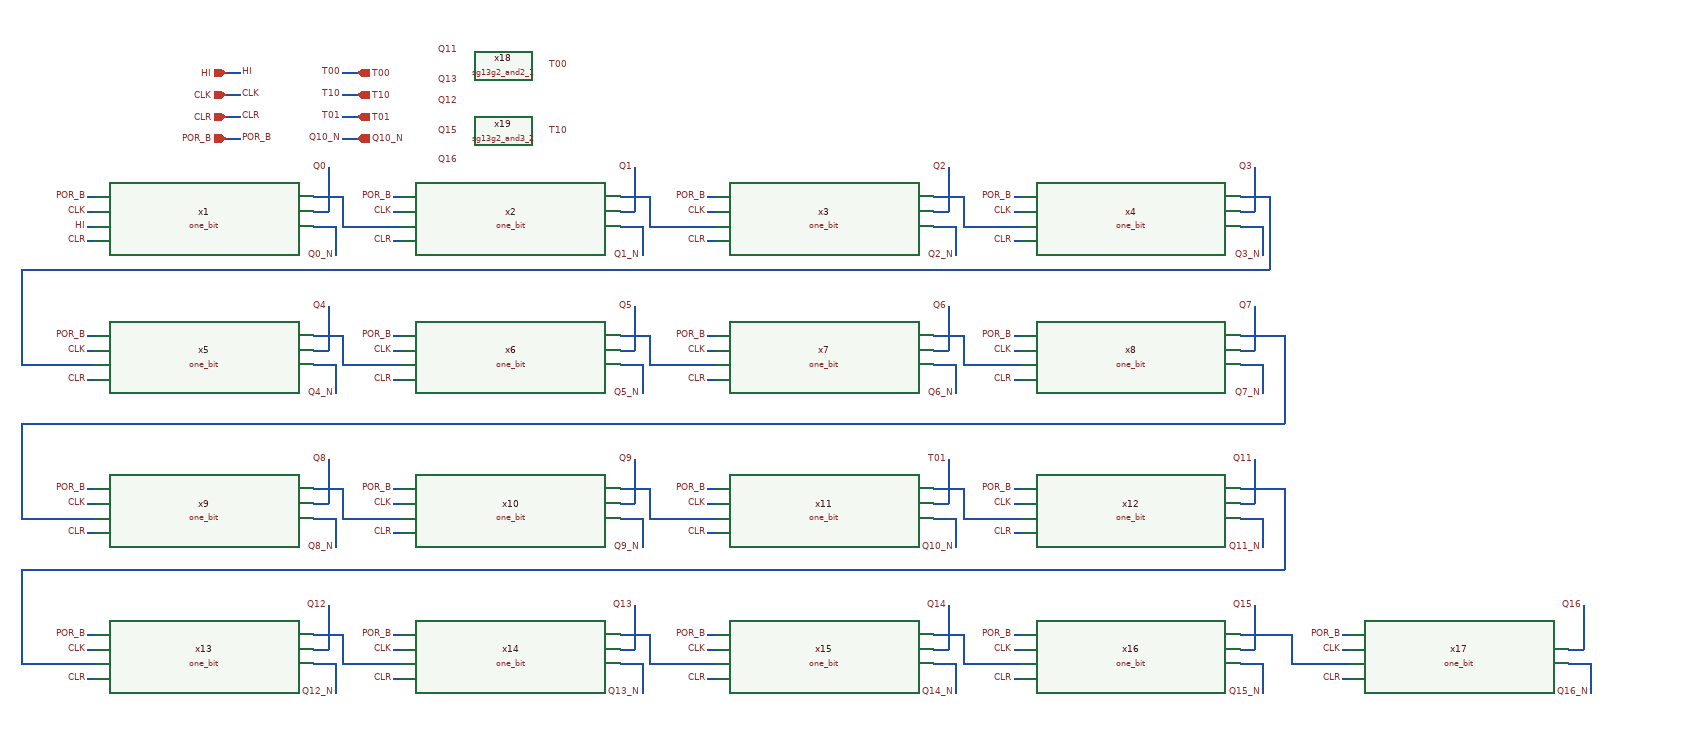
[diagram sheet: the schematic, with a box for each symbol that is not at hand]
v {xschem version=3.4.8RC file_version=1.3}
G {}
K {}
V {}
S {}
F {}
E {}
N -40 -30 0 -30 {lab=#net1}
N -160 -170 -140 -170 {lab=CLK}
N -160 -140 -140 -140 {lab=CLR}
N -160 -110 -140 -110 {lab=POR_B}
N -350 -30 -340 -30 {lab=POR_B}
N -350 -10 -340 -10 {lab=CLK}
N -350 30 -340 30 {lab=CLR}
N -40 -10 -20 -10 {lab=Q0}
N -20 -70 -20 -10 {lab=Q0}
N 380 -30 420 -30 {lab=#net2}
N 70 -30 80 -30 {lab=POR_B}
N 70 -10 80 -10 {lab=CLK}
N 70 30 80 30 {lab=CLR}
N 380 -10 400 -10 {lab=Q1}
N 400 -70 400 -10 {lab=Q1}
N 0 10 80 10 {lab=#net1}
N 0 -30 0 10 {lab=#net1}
N 810 -30 850 -30 {lab=#net3}
N 500 -30 510 -30 {lab=POR_B}
N 500 -10 510 -10 {lab=CLK}
N 500 30 510 30 {lab=CLR}
N 810 -10 830 -10 {lab=Q2}
N 830 -70 830 -10 {lab=Q2}
N 1230 -30 1270 -30 {lab=#net4}
N 920 -30 930 -30 {lab=POR_B}
N 920 -10 930 -10 {lab=CLK}
N 920 30 930 30 {lab=CLR}
N 1230 -10 1250 -10 {lab=Q3}
N 1250 -70 1250 -10 {lab=Q3}
N 850 10 930 10 {lab=#net3}
N 850 -30 850 10 {lab=#net3}
N 420 -30 420 10 {lab=#net2}
N 420 10 510 10 {lab=#net2}
N -40 160 0 160 {lab=#net5}
N -350 160 -340 160 {lab=POR_B}
N -350 180 -340 180 {lab=CLK}
N -350 220 -340 220 {lab=CLR}
N -40 180 -20 180 {lab=Q4}
N -20 120 -20 180 {lab=Q4}
N 380 160 420 160 {lab=#net6}
N 70 160 80 160 {lab=POR_B}
N 70 180 80 180 {lab=CLK}
N 70 220 80 220 {lab=CLR}
N 380 180 400 180 {lab=Q5}
N 400 120 400 180 {lab=Q5}
N 0 200 80 200 {lab=#net5}
N 0 160 0 200 {lab=#net5}
N 810 160 850 160 {lab=#net7}
N 500 160 510 160 {lab=POR_B}
N 500 180 510 180 {lab=CLK}
N 500 220 510 220 {lab=CLR}
N 810 180 830 180 {lab=Q6}
N 830 120 830 180 {lab=Q6}
N 1230 160 1290 160 {lab=#net8}
N 920 160 930 160 {lab=POR_B}
N 920 180 930 180 {lab=CLK}
N 920 220 930 220 {lab=CLR}
N 1230 180 1250 180 {lab=Q7}
N 1250 120 1250 180 {lab=Q7}
N 850 200 930 200 {lab=#net7}
N 850 160 850 200 {lab=#net7}
N 420 160 420 200 {lab=#net6}
N 420 200 510 200 {lab=#net6}
N 1270 -30 1270 70 {lab=#net4}
N -440 70 1270 70 {lab=#net4}
N -440 70 -440 200 {lab=#net4}
N -440 200 -340 200 {lab=#net4}
N -40 10 -10 10 {lab=Q0_N}
N -10 10 -10 50 {lab=Q0_N}
N 380 10 410 10 {lab=Q1_N}
N 410 10 410 50 {lab=Q1_N}
N 810 10 840 10 {lab=Q2_N}
N 840 10 840 50 {lab=Q2_N}
N 1230 10 1260 10 {lab=Q3_N}
N 1260 10 1260 50 {lab=Q3_N}
N 1230 200 1260 200 {lab=Q7_N}
N 1260 200 1260 240 {lab=Q7_N}
N 810 200 840 200 {lab=Q6_N}
N 840 200 840 240 {lab=Q6_N}
N 380 200 410 200 {lab=Q5_N}
N 410 200 410 240 {lab=Q5_N}
N -40 200 -10 200 {lab=Q4_N}
N -10 200 -10 240 {lab=Q4_N}
N -40 370 0 370 {lab=#net9}
N -350 370 -340 370 {lab=POR_B}
N -350 390 -340 390 {lab=CLK}
N -350 430 -340 430 {lab=CLR}
N -40 390 -20 390 {lab=Q8}
N -20 330 -20 390 {lab=Q8}
N 380 370 420 370 {lab=#net10}
N 70 370 80 370 {lab=POR_B}
N 70 390 80 390 {lab=CLK}
N 70 430 80 430 {lab=CLR}
N 380 390 400 390 {lab=Q9}
N 400 330 400 390 {lab=Q9}
N 0 410 80 410 {lab=#net9}
N 0 370 0 410 {lab=#net9}
N 810 370 850 370 {lab=#net11}
N 500 370 510 370 {lab=POR_B}
N 500 390 510 390 {lab=CLK}
N 500 430 510 430 {lab=CLR}
N 810 390 830 390 {lab=Q10}
N 830 330 830 390 {lab=Q10}
N 1230 370 1290 370 {lab=#net12}
N 920 370 930 370 {lab=POR_B}
N 920 390 930 390 {lab=CLK}
N 920 430 930 430 {lab=CLR}
N 1230 390 1250 390 {lab=Q11}
N 1250 330 1250 390 {lab=Q11}
N 850 410 930 410 {lab=#net11}
N 850 370 850 410 {lab=#net11}
N 420 370 420 410 {lab=#net10}
N 420 410 510 410 {lab=#net10}
N -440 280 -440 410 {lab=#net8}
N -440 410 -340 410 {lab=#net8}
N 1230 410 1260 410 {lab=Q11_N}
N 1260 410 1260 450 {lab=Q11_N}
N 810 410 840 410 {lab=Q10_N}
N 840 410 840 450 {lab=Q10_N}
N 380 410 410 410 {lab=Q9_N}
N 410 410 410 450 {lab=Q9_N}
N -40 410 -10 410 {lab=Q8_N}
N -10 410 -10 450 {lab=Q8_N}
N -440 280 1290 280 {lab=#net8}
N 1290 160 1290 280 {lab=#net8}
N -40 570 0 570 {lab=#net13}
N -350 570 -340 570 {lab=POR_B}
N -350 590 -340 590 {lab=CLK}
N -350 630 -340 630 {lab=CLR}
N -40 590 -20 590 {lab=Q12}
N -20 530 -20 590 {lab=Q12}
N 380 570 420 570 {lab=#net14}
N 70 570 80 570 {lab=POR_B}
N 70 590 80 590 {lab=CLK}
N 70 630 80 630 {lab=CLR}
N 380 590 400 590 {lab=Q13}
N 400 530 400 590 {lab=Q13}
N 0 610 80 610 {lab=#net13}
N 0 570 0 610 {lab=#net13}
N 810 570 850 570 {lab=#net15}
N 500 570 510 570 {lab=POR_B}
N 500 590 510 590 {lab=CLK}
N 500 630 510 630 {lab=CLR}
N 810 590 830 590 {lab=Q14}
N 830 530 830 590 {lab=Q14}
N 920 570 930 570 {lab=POR_B}
N 920 590 930 590 {lab=CLK}
N 920 630 930 630 {lab=CLR}
N 1230 590 1250 590 {lab=Q15}
N 1250 530 1250 590 {lab=Q15}
N 850 610 930 610 {lab=#net15}
N 850 570 850 610 {lab=#net15}
N 420 570 420 610 {lab=#net14}
N 420 610 510 610 {lab=#net14}
N -440 480 -440 610 {lab=#net12}
N -440 610 -340 610 {lab=#net12}
N 1230 610 1260 610 {lab=Q15_N}
N 1260 610 1260 650 {lab=Q15_N}
N 810 610 840 610 {lab=Q14_N}
N 840 610 840 650 {lab=Q14_N}
N 380 610 410 610 {lab=Q13_N}
N 410 610 410 650 {lab=Q13_N}
N -40 610 -10 610 {lab=Q12_N}
N -10 610 -10 650 {lab=Q12_N}
N -440 480 1290 480 {lab=#net12}
N 1290 370 1290 480 {lab=#net12}
N 1370 570 1380 570 {lab=POR_B}
N 1370 590 1380 590 {lab=CLK}
N 1370 630 1380 630 {lab=CLR}
N 1680 590 1700 590 {lab=Q16}
N 1700 530 1700 590 {lab=Q16}
N 1300 610 1380 610 {lab=#net16}
N 1300 570 1300 610 {lab=#net16}
N 1680 610 1710 610 {lab=Q16_N}
N 1710 610 1710 650 {lab=Q16_N}
N 1230 570 1300 570 {lab=#net16}
N -160 -200 -140 -200 {lab=HI}
N -350 10 -340 10 {lab=HI}
N 0 -200 20 -200 {lab=T00}
N 0 -170 20 -170 {lab=T10}
N 0 -140 20 -140 {lab=T01}
N 0 -110 20 -110 {lab=Q10_N}
C {one_bit.sym} -190 0 0 0 {name=x1 VDD=VDD VSS=VSS}
C {lab_pin.sym} -140 -170 0 1 {name=p12 sig_type=std_logic lab=CLK
}
C {ipin.sym} -160 -170 0 0 {name=p13 lab=CLK}
C {lab_pin.sym} -140 -140 0 1 {name=p1 sig_type=std_logic lab=CLR
}
C {ipin.sym} -160 -140 0 0 {name=p2 lab=CLR}
C {lab_pin.sym} -140 -110 0 1 {name=p3 sig_type=std_logic lab=POR_B
}
C {ipin.sym} -160 -110 0 0 {name=p4 lab=POR_B}
C {lab_pin.sym} -350 -30 0 0 {name=p5 sig_type=std_logic lab=POR_B
}
C {lab_pin.sym} -350 30 0 0 {name=p6 sig_type=std_logic lab=CLR
}
C {lab_pin.sym} -350 -10 0 0 {name=p7 sig_type=std_logic lab=CLK
}
C {lab_pin.sym} -20 -70 0 0 {name=p8 sig_type=std_logic lab=Q0
}
C {one_bit.sym} 230 0 0 0 {name=x2 VDD=VDD VSS=VSS}
C {lab_pin.sym} 70 -30 0 0 {name=p9 sig_type=std_logic lab=POR_B
}
C {lab_pin.sym} 70 30 0 0 {name=p10 sig_type=std_logic lab=CLR
}
C {lab_pin.sym} 70 -10 0 0 {name=p11 sig_type=std_logic lab=CLK
}
C {lab_pin.sym} 400 -70 0 0 {name=p14 sig_type=std_logic lab=Q1
}
C {one_bit.sym} 660 0 0 0 {name=x3 VDD=VDD VSS=VSS}
C {lab_pin.sym} 500 -30 0 0 {name=p15 sig_type=std_logic lab=POR_B
}
C {lab_pin.sym} 500 30 0 0 {name=p16 sig_type=std_logic lab=CLR
}
C {lab_pin.sym} 500 -10 0 0 {name=p17 sig_type=std_logic lab=CLK
}
C {lab_pin.sym} 830 -70 0 0 {name=p18 sig_type=std_logic lab=Q2
}
C {one_bit.sym} 1080 0 0 0 {name=x4 VDD=VDD VSS=VSS}
C {lab_pin.sym} 920 -30 0 0 {name=p19 sig_type=std_logic lab=POR_B
}
C {lab_pin.sym} 920 30 0 0 {name=p20 sig_type=std_logic lab=CLR
}
C {lab_pin.sym} 920 -10 0 0 {name=p21 sig_type=std_logic lab=CLK
}
C {lab_pin.sym} 1250 -70 0 0 {name=p22 sig_type=std_logic lab=Q3
}
C {one_bit.sym} -190 190 0 0 {name=x5 VDD=VDD VSS=VSS}
C {lab_pin.sym} -350 160 0 0 {name=p23 sig_type=std_logic lab=POR_B
}
C {lab_pin.sym} -350 220 0 0 {name=p24 sig_type=std_logic lab=CLR
}
C {lab_pin.sym} -350 180 0 0 {name=p25 sig_type=std_logic lab=CLK
}
C {lab_pin.sym} -20 120 0 0 {name=p26 sig_type=std_logic lab=Q4
}
C {one_bit.sym} 230 190 0 0 {name=x6 VDD=VDD VSS=VSS}
C {lab_pin.sym} 70 160 0 0 {name=p27 sig_type=std_logic lab=POR_B
}
C {lab_pin.sym} 70 220 0 0 {name=p28 sig_type=std_logic lab=CLR
}
C {lab_pin.sym} 70 180 0 0 {name=p29 sig_type=std_logic lab=CLK
}
C {lab_pin.sym} 400 120 0 0 {name=p30 sig_type=std_logic lab=Q5
}
C {one_bit.sym} 660 190 0 0 {name=x7 VDD=VDD VSS=VSS}
C {lab_pin.sym} 500 160 0 0 {name=p31 sig_type=std_logic lab=POR_B
}
C {lab_pin.sym} 500 220 0 0 {name=p32 sig_type=std_logic lab=CLR
}
C {lab_pin.sym} 500 180 0 0 {name=p33 sig_type=std_logic lab=CLK
}
C {lab_pin.sym} 830 120 0 0 {name=p34 sig_type=std_logic lab=Q6
}
C {one_bit.sym} 1080 190 0 0 {name=x8 VDD=VDD VSS=VSS}
C {lab_pin.sym} 920 160 0 0 {name=p35 sig_type=std_logic lab=POR_B
}
C {lab_pin.sym} 920 220 0 0 {name=p36 sig_type=std_logic lab=CLR
}
C {lab_pin.sym} 920 180 0 0 {name=p37 sig_type=std_logic lab=CLK
}
C {lab_pin.sym} 1250 120 0 0 {name=p38 sig_type=std_logic lab=Q7
}
C {lab_pin.sym} -10 50 0 0 {name=p39 sig_type=std_logic lab=Q0_N
}
C {lab_pin.sym} 410 50 0 0 {name=p40 sig_type=std_logic lab=Q1_N
}
C {lab_pin.sym} 840 50 0 0 {name=p41 sig_type=std_logic lab=Q2_N
}
C {lab_pin.sym} 1260 50 0 0 {name=p42 sig_type=std_logic lab=Q3_N
}
C {lab_pin.sym} 1260 240 0 0 {name=p43 sig_type=std_logic lab=Q7_N
}
C {lab_pin.sym} 840 240 0 0 {name=p44 sig_type=std_logic lab=Q6_N
}
C {lab_pin.sym} 410 240 0 0 {name=p45 sig_type=std_logic lab=Q5_N
}
C {lab_pin.sym} -10 240 0 0 {name=p46 sig_type=std_logic lab=Q4_N
}
C {one_bit.sym} -190 400 0 0 {name=x9 VDD=VDD VSS=VSS}
C {lab_pin.sym} -350 370 0 0 {name=p47 sig_type=std_logic lab=POR_B
}
C {lab_pin.sym} -350 430 0 0 {name=p48 sig_type=std_logic lab=CLR
}
C {lab_pin.sym} -350 390 0 0 {name=p49 sig_type=std_logic lab=CLK
}
C {lab_pin.sym} -20 330 0 0 {name=p50 sig_type=std_logic lab=Q8
}
C {one_bit.sym} 230 400 0 0 {name=x10 VDD=VDD VSS=VSS}
C {lab_pin.sym} 70 370 0 0 {name=p51 sig_type=std_logic lab=POR_B
}
C {lab_pin.sym} 70 430 0 0 {name=p52 sig_type=std_logic lab=CLR
}
C {lab_pin.sym} 70 390 0 0 {name=p53 sig_type=std_logic lab=CLK
}
C {lab_pin.sym} 400 330 0 0 {name=p54 sig_type=std_logic lab=Q9
}
C {one_bit.sym} 660 400 0 0 {name=x11 VDD=VDD VSS=VSS}
C {lab_pin.sym} 500 370 0 0 {name=p55 sig_type=std_logic lab=POR_B
}
C {lab_pin.sym} 500 430 0 0 {name=p56 sig_type=std_logic lab=CLR
}
C {lab_pin.sym} 500 390 0 0 {name=p57 sig_type=std_logic lab=CLK
}
C {lab_pin.sym} 830 330 0 0 {name=p58 sig_type=std_logic lab=T01
}
C {one_bit.sym} 1080 400 0 0 {name=x12 VDD=VDD VSS=VSS}
C {lab_pin.sym} 920 370 0 0 {name=p59 sig_type=std_logic lab=POR_B
}
C {lab_pin.sym} 920 430 0 0 {name=p60 sig_type=std_logic lab=CLR
}
C {lab_pin.sym} 920 390 0 0 {name=p61 sig_type=std_logic lab=CLK
}
C {lab_pin.sym} 1250 330 0 0 {name=p62 sig_type=std_logic lab=Q11
}
C {lab_pin.sym} 1260 450 0 0 {name=p63 sig_type=std_logic lab=Q11_N
}
C {lab_pin.sym} 840 450 0 0 {name=p64 sig_type=std_logic lab=Q10_N
}
C {lab_pin.sym} 410 450 0 0 {name=p65 sig_type=std_logic lab=Q9_N
}
C {lab_pin.sym} -10 450 0 0 {name=p66 sig_type=std_logic lab=Q8_N
}
C {one_bit.sym} -190 600 0 0 {name=x13 VDD=VDD VSS=VSS}
C {lab_pin.sym} -350 570 0 0 {name=p67 sig_type=std_logic lab=POR_B
}
C {lab_pin.sym} -350 630 0 0 {name=p68 sig_type=std_logic lab=CLR
}
C {lab_pin.sym} -350 590 0 0 {name=p69 sig_type=std_logic lab=CLK
}
C {lab_pin.sym} -20 530 0 0 {name=p70 sig_type=std_logic lab=Q12

}
C {one_bit.sym} 230 600 0 0 {name=x14 VDD=VDD VSS=VSS}
C {lab_pin.sym} 70 570 0 0 {name=p71 sig_type=std_logic lab=POR_B
}
C {lab_pin.sym} 70 630 0 0 {name=p72 sig_type=std_logic lab=CLR
}
C {lab_pin.sym} 70 590 0 0 {name=p73 sig_type=std_logic lab=CLK
}
C {lab_pin.sym} 400 530 0 0 {name=p74 sig_type=std_logic lab=Q13
}
C {one_bit.sym} 660 600 0 0 {name=x15 VDD=VDD VSS=VSS}
C {lab_pin.sym} 500 570 0 0 {name=p75 sig_type=std_logic lab=POR_B
}
C {lab_pin.sym} 500 630 0 0 {name=p76 sig_type=std_logic lab=CLR
}
C {lab_pin.sym} 500 590 0 0 {name=p77 sig_type=std_logic lab=CLK
}
C {lab_pin.sym} 830 530 0 0 {name=p78 sig_type=std_logic lab=Q14
}
C {one_bit.sym} 1080 600 0 0 {name=x16 VDD=VDD VSS=VSS}
C {lab_pin.sym} 920 570 0 0 {name=p79 sig_type=std_logic lab=POR_B
}
C {lab_pin.sym} 920 630 0 0 {name=p80 sig_type=std_logic lab=CLR
}
C {lab_pin.sym} 920 590 0 0 {name=p81 sig_type=std_logic lab=CLK
}
C {lab_pin.sym} 1250 530 0 0 {name=p82 sig_type=std_logic lab=Q15
}
C {lab_pin.sym} 1260 650 0 0 {name=p83 sig_type=std_logic lab=Q15_N
}
C {lab_pin.sym} 840 650 0 0 {name=p84 sig_type=std_logic lab=Q14_N
}
C {lab_pin.sym} 410 650 0 0 {name=p85 sig_type=std_logic lab=Q13_N
}
C {lab_pin.sym} -10 650 0 0 {name=p86 sig_type=std_logic lab=Q12_N
}
C {one_bit.sym} 1530 600 0 0 {name=x17 VDD=VDD VSS=VSS}
C {lab_pin.sym} 1370 570 0 0 {name=p87 sig_type=std_logic lab=POR_B
}
C {lab_pin.sym} 1370 630 0 0 {name=p88 sig_type=std_logic lab=CLR
}
C {lab_pin.sym} 1370 590 0 0 {name=p89 sig_type=std_logic lab=CLK
}
C {lab_pin.sym} 1700 530 0 0 {name=p90 sig_type=std_logic lab=Q16
}
C {lab_pin.sym} 1710 650 0 0 {name=p91 sig_type=std_logic lab=Q16_N
}
C {lab_pin.sym} -140 -200 0 1 {name=p92 sig_type=std_logic lab=HI
}
C {ipin.sym} -160 -200 0 0 {name=p93 lab=HI}
C {lab_pin.sym} -350 10 0 0 {name=p94 sig_type=std_logic lab=HI
}
C {sg13g2_and2_1.sym} 220 -210 0 0 {name=x18 VDD=VDD VSS=VSS prefix=sg13g2_ }
C {lab_pin.sym} 160 -230 0 0 {name=p95 sig_type=std_logic lab=Q11
}
C {lab_pin.sym} 160 -190 0 0 {name=p96 sig_type=std_logic lab=Q13}
C {sg13g2_and3_2.sym} 220 -120 0 0 {name=x19 VDD=VDD VSS=VSS prefix=sg13g2_ }
C {lab_pin.sym} 160 -160 0 0 {name=p97 sig_type=std_logic lab=Q12
}
C {lab_pin.sym} 160 -120 0 0 {name=p98 sig_type=std_logic lab=Q15
}
C {lab_pin.sym} 160 -80 0 0 {name=p99 sig_type=std_logic lab=Q16
}
C {lab_pin.sym} 280 -210 0 1 {name=p100 sig_type=std_logic lab=T00
}
C {lab_pin.sym} 280 -120 0 1 {name=p101 sig_type=std_logic lab=T10
}
C {opin.sym} 20 -200 0 0 {name=p102 lab=T00}
C {lab_pin.sym} 0 -200 0 0 {name=p103 sig_type=std_logic lab=T00
}
C {opin.sym} 20 -170 0 0 {name=p104 lab=T10}
C {lab_pin.sym} 0 -170 0 0 {name=p105 sig_type=std_logic lab=T10
}
C {opin.sym} 20 -140 0 0 {name=p106 lab=T01}
C {lab_pin.sym} 0 -140 0 0 {name=p107 sig_type=std_logic lab=T01
}
C {opin.sym} 20 -110 0 0 {name=p108 lab=Q10_N}
C {lab_pin.sym} 0 -110 0 0 {name=p109 sig_type=std_logic lab=Q10_N
}
